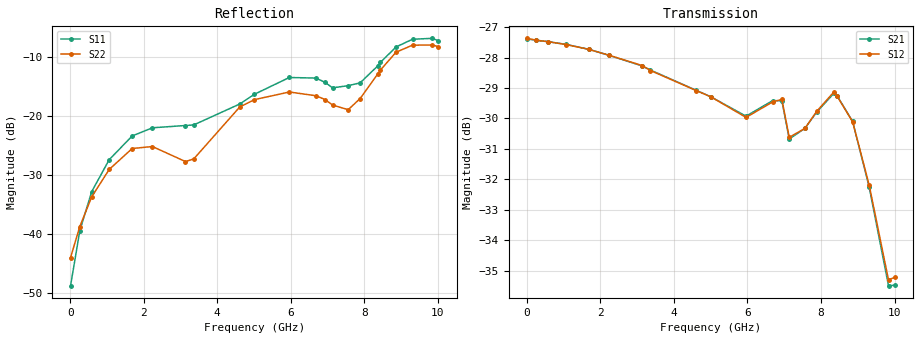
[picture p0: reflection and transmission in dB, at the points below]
! Device ID: PE43704
! Dir: z:\PE43704\PE43704_Char_1_20130516\PE43704\AMB\3p400V\26p50dB
! Serial: 14
! Insertion: A
! Impedance: 50 ohm
! Temp: Amb
! VDD: 3.400V
! Attenuation Step: 26.50dB
! IDD: 1.141536e-01mA
#  Hz  S  RI  R  50
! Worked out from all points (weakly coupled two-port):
!   401 points, 10 MHz to 10.01 GHz, reference 50 ohm
!   highest |S21| = -27.40 dB at 10 MHz (marker M1); lowest = -35.5 dB at 9.835 GHz (marker M2)
!   lowest |S11| = -48.8 dB at 10 MHz (marker M3), VSWR 1.01, Z = 50.4 + j0.04 ohm
!   |S11| at or under -10 dB: start of sweep to 8.562 GHz
!   |S22| runs from -44.0 to -7.8 dB; largest |S21 - S12| = 0.00076
!   S11 on the Smith chart (normalised r, x): 10 MHz: 1.01, +0.00; 4.61 GHz: 0.79, +0.08; 8.435 GHz: 0.76, +0.46; 9.31 GHz: 0.51, +0.52; 10.01 GHz: 0.44, +0.31
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1e7  0.00363 0.000397  0.0427 -0.000144  0.0428 -0.000129  0.00632 0.000376
2.6e8  0.00115 0.0106  0.0424 -0.00285  0.0424 -0.00286  0.00441 0.0107
5.85e8  -0.00964 0.0208  0.0418 -0.0062  0.0418 -0.00622  -0.00539 0.02
1.06e9  -0.0359 0.0232  0.0404 -0.0109  0.0404 -0.0108  -0.0287 0.0206
1.685e9  -0.0676 0.00645  0.0376 -0.0165  0.0376 -0.0165  -0.0531 0.00239
2.235e9  -0.0788 -0.0119  0.0344 -0.0207  0.0344 -0.0207  -0.0539 -0.0123
3.135e9  -0.0816 -0.0168  0.0282 -0.0263  0.0282 -0.0264  -0.0411 -0.00296
3.36e9  -0.0836 -0.0109  0.0265 -0.0272  0.0264 -0.0272  -0.0431 0.00506
4.61e9  -0.1166 0.0498  0.0175 -0.0305  0.0176 -0.0304  -0.1049 0.0574
5.01e9  -0.136 0.0709  0.0155 -0.0306  0.0155 -0.0306  -0.1258 0.0569
5.96e9  -0.1865 0.1025  0.00935 -0.0305  0.00948 -0.0303  -0.1508 0.0544
6.685e9  -0.1871 0.0962  0.00653 -0.0332  0.00665 -0.033  -0.1392 0.053
6.935e9  -0.1699 0.0918  0.00267 -0.0337  0.00242 -0.0339  -0.124 0.0608
7.135e9  -0.1547 0.0794  0.00181 -0.0292  0.00171 -0.0294  -0.1043 0.0675
7.56e9  -0.1297 0.1269  0.0019 -0.0304  0.00183 -0.0304  -0.0683 0.0906
7.885e9  -0.0904 0.1689  0.000767 -0.0324  0.000568 -0.0325  -0.0576 0.1288
8.36e9  -0.0599 0.2593  -0.00708 -0.0341  -0.00702 -0.0343  -0.0734 0.215
8.435e9  -0.061 0.2787  -0.00853 -0.0334  -0.0083 -0.0334  -0.0817 0.2317
8.86e9  -0.1006 0.3728  -0.0143 -0.0278  -0.0144 -0.0277  -0.1381 0.3198
9.31e9  -0.1829 0.41  -0.0141 -0.0199  -0.014 -0.0202  -0.2226 0.3323
9.835e9  -0.3004 0.3441  -0.00674 -0.0154  -0.00719 -0.0156  -0.3312 0.2264
1.001e10  -0.329 0.2887  -0.00335 -0.0165  -0.00398 -0.0169  -0.353 0.1636
